VERSION 5.7 ;
  NOWIREEXTENSIONATPIN ON ;
  DIVIDERCHAR "/" ;
  BUSBITCHARS "[]" ;
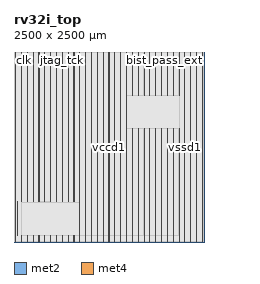
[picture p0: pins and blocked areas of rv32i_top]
MACRO rv32i_top
  CLASS BLOCK ;
  FOREIGN rv32i_top ;
  ORIGIN 0.000 0.000 ;
  SIZE 2500.000 BY 2500.000 ;
  PIN bist_done_ext
    DIRECTION OUTPUT TRISTATE ;
    USE SIGNAL ;
    ANTENNADIFFAREA 0.795200 ;
    PORT
      LAYER met2 ;
        RECT 2123.910 2496.000 2124.190 2500.000 ;
    END
  END bist_done_ext
  PIN bist_mode_ext
    DIRECTION INPUT ;
    USE SIGNAL ;
    ANTENNAGATEAREA 0.990000 ;
    PORT
      LAYER met2 ;
        RECT 1874.130 2496.000 1874.410 2500.000 ;
    END
  END bist_mode_ext
  PIN bist_pass_ext
    DIRECTION OUTPUT TRISTATE ;
    USE SIGNAL ;
    ANTENNADIFFAREA 0.795200 ;
    PORT
      LAYER met2 ;
        RECT 2373.690 2496.000 2373.970 2500.000 ;
    END
  END bist_pass_ext
  PIN clk
    DIRECTION INPUT ;
    USE SIGNAL ;
    ANTENNAGATEAREA 2.156100 ;
    ANTENNADIFFAREA 1.304100 ;
    PORT
      LAYER met2 ;
        RECT 125.670 2496.000 125.950 2500.000 ;
    END
  END clk
  PIN jtag_tck
    DIRECTION INPUT ;
    USE SIGNAL ;
    ANTENNAGATEAREA 0.990000 ;
    PORT
      LAYER met2 ;
        RECT 625.230 2496.000 625.510 2500.000 ;
    END
  END jtag_tck
  PIN jtag_tdi
    DIRECTION INPUT ;
    USE SIGNAL ;
    ANTENNAGATEAREA 0.742500 ;
    PORT
      LAYER met2 ;
        RECT 1124.790 2496.000 1125.070 2500.000 ;
    END
  END jtag_tdi
  PIN jtag_tdo
    DIRECTION OUTPUT TRISTATE ;
    USE SIGNAL ;
    ANTENNADIFFAREA 0.795200 ;
    PORT
      LAYER met2 ;
        RECT 1374.570 2496.000 1374.850 2500.000 ;
    END
  END jtag_tdo
  PIN jtag_tms
    DIRECTION INPUT ;
    USE SIGNAL ;
    ANTENNAGATEAREA 0.742500 ;
    PORT
      LAYER met2 ;
        RECT 875.010 2496.000 875.290 2500.000 ;
    END
  END jtag_tms
  PIN jtag_trst_n
    DIRECTION INPUT ;
    USE SIGNAL ;
    ANTENNAGATEAREA 0.990000 ;
    PORT
      LAYER met2 ;
        RECT 1624.350 2496.000 1624.630 2500.000 ;
    END
  END jtag_trst_n
  PIN rst_n
    DIRECTION INPUT ;
    USE SIGNAL ;
    ANTENNAGATEAREA 0.742500 ;
    PORT
      LAYER met2 ;
        RECT 375.450 2496.000 375.730 2500.000 ;
    END
  END rst_n
  PIN vccd1
    DIRECTION INOUT ;
    USE POWER ;
    PORT
      LAYER met4 ;
        RECT 21.040 10.640 22.640 2489.040 ;
    END
    PORT
      LAYER met4 ;
        RECT 174.640 10.640 176.240 90.020 ;
    END
    PORT
      LAYER met4 ;
        RECT 174.640 526.520 176.240 2489.040 ;
    END
    PORT
      LAYER met4 ;
        RECT 328.240 10.640 329.840 89.400 ;
    END
    PORT
      LAYER met4 ;
        RECT 328.240 526.520 329.840 2489.040 ;
    END
    PORT
      LAYER met4 ;
        RECT 481.840 10.640 483.440 90.020 ;
    END
    PORT
      LAYER met4 ;
        RECT 481.840 526.520 483.440 2489.040 ;
    END
    PORT
      LAYER met4 ;
        RECT 635.440 10.640 637.040 90.020 ;
    END
    PORT
      LAYER met4 ;
        RECT 635.440 526.520 637.040 2489.040 ;
    END
    PORT
      LAYER met4 ;
        RECT 789.040 10.640 790.640 90.020 ;
    END
    PORT
      LAYER met4 ;
        RECT 789.040 526.520 790.640 2489.040 ;
    END
    PORT
      LAYER met4 ;
        RECT 942.640 10.640 944.240 2489.040 ;
    END
    PORT
      LAYER met4 ;
        RECT 1096.240 10.640 1097.840 2489.040 ;
    END
    PORT
      LAYER met4 ;
        RECT 1249.840 10.640 1251.440 2489.040 ;
    END
    PORT
      LAYER met4 ;
        RECT 1403.440 10.640 1405.040 2489.040 ;
    END
    PORT
      LAYER met4 ;
        RECT 1557.040 10.640 1558.640 1490.020 ;
    END
    PORT
      LAYER met4 ;
        RECT 1557.040 1926.520 1558.640 2489.040 ;
    END
    PORT
      LAYER met4 ;
        RECT 1710.640 10.640 1712.240 1490.020 ;
    END
    PORT
      LAYER met4 ;
        RECT 1710.640 1926.520 1712.240 2489.040 ;
    END
    PORT
      LAYER met4 ;
        RECT 1864.240 10.640 1865.840 1490.020 ;
    END
    PORT
      LAYER met4 ;
        RECT 1864.240 1926.520 1865.840 2489.040 ;
    END
    PORT
      LAYER met4 ;
        RECT 2017.840 10.640 2019.440 1490.020 ;
    END
    PORT
      LAYER met4 ;
        RECT 2017.840 1926.520 2019.440 2489.040 ;
    END
    PORT
      LAYER met4 ;
        RECT 2171.440 10.640 2173.040 1490.020 ;
    END
    PORT
      LAYER met4 ;
        RECT 2171.440 1926.520 2173.040 2489.040 ;
    END
    PORT
      LAYER met4 ;
        RECT 2325.040 10.640 2326.640 2489.040 ;
    END
    PORT
      LAYER met4 ;
        RECT 2478.640 10.640 2480.240 2489.040 ;
    END
  END vccd1
  PIN vssd1
    DIRECTION INOUT ;
    USE GROUND ;
    PORT
      LAYER met4 ;
        RECT 97.840 10.640 99.440 90.020 ;
    END
    PORT
      LAYER met4 ;
        RECT 97.840 526.520 99.440 2489.040 ;
    END
    PORT
      LAYER met4 ;
        RECT 251.440 10.640 253.040 90.020 ;
    END
    PORT
      LAYER met4 ;
        RECT 251.440 526.520 253.040 2489.040 ;
    END
    PORT
      LAYER met4 ;
        RECT 405.040 10.640 406.640 89.400 ;
    END
    PORT
      LAYER met4 ;
        RECT 405.040 527.140 406.640 2489.040 ;
    END
    PORT
      LAYER met4 ;
        RECT 558.640 10.640 560.240 90.020 ;
    END
    PORT
      LAYER met4 ;
        RECT 558.640 526.520 560.240 2489.040 ;
    END
    PORT
      LAYER met4 ;
        RECT 712.240 10.640 713.840 90.020 ;
    END
    PORT
      LAYER met4 ;
        RECT 712.240 526.520 713.840 2489.040 ;
    END
    PORT
      LAYER met4 ;
        RECT 865.840 10.640 867.440 2489.040 ;
    END
    PORT
      LAYER met4 ;
        RECT 1019.440 10.640 1021.040 2489.040 ;
    END
    PORT
      LAYER met4 ;
        RECT 1173.040 10.640 1174.640 2489.040 ;
    END
    PORT
      LAYER met4 ;
        RECT 1326.640 10.640 1328.240 2489.040 ;
    END
    PORT
      LAYER met4 ;
        RECT 1480.240 10.640 1481.840 2489.040 ;
    END
    PORT
      LAYER met4 ;
        RECT 1633.840 10.640 1635.440 1490.020 ;
    END
    PORT
      LAYER met4 ;
        RECT 1633.840 1926.520 1635.440 2489.040 ;
    END
    PORT
      LAYER met4 ;
        RECT 1787.440 10.640 1789.040 1490.020 ;
    END
    PORT
      LAYER met4 ;
        RECT 1787.440 1926.520 1789.040 2489.040 ;
    END
    PORT
      LAYER met4 ;
        RECT 1941.040 10.640 1942.640 1489.400 ;
    END
    PORT
      LAYER met4 ;
        RECT 1941.040 1927.140 1942.640 2489.040 ;
    END
    PORT
      LAYER met4 ;
        RECT 2094.640 10.640 2096.240 1490.020 ;
    END
    PORT
      LAYER met4 ;
        RECT 2094.640 1926.520 2096.240 2489.040 ;
    END
    PORT
      LAYER met4 ;
        RECT 2248.240 10.640 2249.840 2489.040 ;
    END
    PORT
      LAYER met4 ;
        RECT 2401.840 10.640 2403.440 2489.040 ;
    END
    PORT
      LAYER met4 ;
        RECT 46.580 86.800 48.180 527.920 ;
    END
  END vssd1
  OBS
      LAYER nwell ;
        RECT 5.330 2487.385 2494.310 2488.990 ;
        RECT 5.330 2481.945 2494.310 2484.775 ;
        RECT 5.330 2476.505 2494.310 2479.335 ;
        RECT 5.330 2471.065 2494.310 2473.895 ;
        RECT 5.330 2465.625 2494.310 2468.455 ;
        RECT 5.330 2460.185 2494.310 2463.015 ;
        RECT 5.330 2454.745 2494.310 2457.575 ;
        RECT 5.330 2449.305 2494.310 2452.135 ;
        RECT 5.330 2443.865 2494.310 2446.695 ;
        RECT 5.330 2438.425 2494.310 2441.255 ;
        RECT 5.330 2432.985 2494.310 2435.815 ;
        RECT 5.330 2427.545 2494.310 2430.375 ;
        RECT 5.330 2422.105 2494.310 2424.935 ;
        RECT 5.330 2416.665 2494.310 2419.495 ;
        RECT 5.330 2411.225 2494.310 2414.055 ;
        RECT 5.330 2405.785 2494.310 2408.615 ;
        RECT 5.330 2400.345 2494.310 2403.175 ;
        RECT 5.330 2394.905 2494.310 2397.735 ;
        RECT 5.330 2389.465 2494.310 2392.295 ;
        RECT 5.330 2384.025 2494.310 2386.855 ;
        RECT 5.330 2378.585 2494.310 2381.415 ;
        RECT 5.330 2373.145 2494.310 2375.975 ;
        RECT 5.330 2367.705 2494.310 2370.535 ;
        RECT 5.330 2362.265 2494.310 2365.095 ;
        RECT 5.330 2356.825 2494.310 2359.655 ;
        RECT 5.330 2351.385 2494.310 2354.215 ;
        RECT 5.330 2345.945 2494.310 2348.775 ;
        RECT 5.330 2340.505 2494.310 2343.335 ;
        RECT 5.330 2335.065 2494.310 2337.895 ;
        RECT 5.330 2329.625 2494.310 2332.455 ;
        RECT 5.330 2324.185 2494.310 2327.015 ;
        RECT 5.330 2318.745 2494.310 2321.575 ;
        RECT 5.330 2313.305 2494.310 2316.135 ;
        RECT 5.330 2307.865 2494.310 2310.695 ;
        RECT 5.330 2302.425 2494.310 2305.255 ;
        RECT 5.330 2296.985 2494.310 2299.815 ;
        RECT 5.330 2291.545 2494.310 2294.375 ;
        RECT 5.330 2286.105 2494.310 2288.935 ;
        RECT 5.330 2280.665 2494.310 2283.495 ;
        RECT 5.330 2275.225 2494.310 2278.055 ;
        RECT 5.330 2269.785 2494.310 2272.615 ;
        RECT 5.330 2264.345 2494.310 2267.175 ;
        RECT 5.330 2258.905 2494.310 2261.735 ;
        RECT 5.330 2253.465 2494.310 2256.295 ;
        RECT 5.330 2248.025 2494.310 2250.855 ;
        RECT 5.330 2242.585 2494.310 2245.415 ;
        RECT 5.330 2237.145 2494.310 2239.975 ;
        RECT 5.330 2231.705 2494.310 2234.535 ;
        RECT 5.330 2226.265 2494.310 2229.095 ;
        RECT 5.330 2220.825 2494.310 2223.655 ;
        RECT 5.330 2215.385 2494.310 2218.215 ;
        RECT 5.330 2209.945 2494.310 2212.775 ;
        RECT 5.330 2204.505 2494.310 2207.335 ;
        RECT 5.330 2199.065 2494.310 2201.895 ;
        RECT 5.330 2193.625 2494.310 2196.455 ;
        RECT 5.330 2188.185 2494.310 2191.015 ;
        RECT 5.330 2182.745 2494.310 2185.575 ;
        RECT 5.330 2177.305 2494.310 2180.135 ;
        RECT 5.330 2171.865 2494.310 2174.695 ;
        RECT 5.330 2166.425 2494.310 2169.255 ;
        RECT 5.330 2160.985 2494.310 2163.815 ;
        RECT 5.330 2155.545 2494.310 2158.375 ;
        RECT 5.330 2150.105 2494.310 2152.935 ;
        RECT 5.330 2144.665 2494.310 2147.495 ;
        RECT 5.330 2139.225 2494.310 2142.055 ;
        RECT 5.330 2133.785 2494.310 2136.615 ;
        RECT 5.330 2128.345 2494.310 2131.175 ;
        RECT 5.330 2122.905 2494.310 2125.735 ;
        RECT 5.330 2117.465 2494.310 2120.295 ;
        RECT 5.330 2112.025 2494.310 2114.855 ;
        RECT 5.330 2106.585 2494.310 2109.415 ;
        RECT 5.330 2101.145 2494.310 2103.975 ;
        RECT 5.330 2095.705 2494.310 2098.535 ;
        RECT 5.330 2090.265 2494.310 2093.095 ;
        RECT 5.330 2084.825 2494.310 2087.655 ;
        RECT 5.330 2079.385 2494.310 2082.215 ;
        RECT 5.330 2073.945 2494.310 2076.775 ;
        RECT 5.330 2068.505 2494.310 2071.335 ;
        RECT 5.330 2063.065 2494.310 2065.895 ;
        RECT 5.330 2057.625 2494.310 2060.455 ;
        RECT 5.330 2052.185 2494.310 2055.015 ;
        RECT 5.330 2046.745 2494.310 2049.575 ;
        RECT 5.330 2041.305 2494.310 2044.135 ;
        RECT 5.330 2035.865 2494.310 2038.695 ;
        RECT 5.330 2030.425 2494.310 2033.255 ;
        RECT 5.330 2024.985 2494.310 2027.815 ;
        RECT 5.330 2019.545 2494.310 2022.375 ;
        RECT 5.330 2014.105 2494.310 2016.935 ;
        RECT 5.330 2008.665 2494.310 2011.495 ;
        RECT 5.330 2003.225 2494.310 2006.055 ;
        RECT 5.330 1997.785 2494.310 2000.615 ;
        RECT 5.330 1992.345 2494.310 1995.175 ;
        RECT 5.330 1986.905 2494.310 1989.735 ;
        RECT 5.330 1981.465 2494.310 1984.295 ;
        RECT 5.330 1976.025 2494.310 1978.855 ;
        RECT 5.330 1970.585 2494.310 1973.415 ;
        RECT 5.330 1965.145 2494.310 1967.975 ;
        RECT 5.330 1959.705 2494.310 1962.535 ;
        RECT 5.330 1954.265 2494.310 1957.095 ;
        RECT 5.330 1948.825 2494.310 1951.655 ;
        RECT 5.330 1943.385 2494.310 1946.215 ;
        RECT 5.330 1937.945 2494.310 1940.775 ;
        RECT 5.330 1932.505 2494.310 1935.335 ;
        RECT 5.330 1928.290 2494.310 1929.895 ;
        RECT 5.330 1927.065 1490.130 1928.290 ;
        RECT 5.330 1921.625 1490.130 1924.455 ;
        RECT 5.330 1916.185 1490.130 1919.015 ;
        RECT 5.330 1910.745 1490.130 1913.575 ;
        RECT 5.330 1905.305 1490.130 1908.135 ;
        RECT 5.330 1899.865 1490.130 1902.695 ;
        RECT 5.330 1894.425 1490.130 1897.255 ;
        RECT 5.330 1888.985 1490.130 1891.815 ;
        RECT 5.330 1883.545 1490.130 1886.375 ;
        RECT 5.330 1878.105 1490.130 1880.935 ;
        RECT 5.330 1872.665 1490.130 1875.495 ;
        RECT 5.330 1867.225 1490.130 1870.055 ;
        RECT 5.330 1861.785 1490.130 1864.615 ;
        RECT 5.330 1856.345 1490.130 1859.175 ;
        RECT 5.330 1850.905 1490.130 1853.735 ;
        RECT 5.330 1845.465 1490.130 1848.295 ;
        RECT 5.330 1840.025 1490.130 1842.855 ;
        RECT 5.330 1834.585 1490.130 1837.415 ;
        RECT 5.330 1829.145 1490.130 1831.975 ;
        RECT 5.330 1823.705 1490.130 1826.535 ;
        RECT 5.330 1818.265 1490.130 1821.095 ;
        RECT 5.330 1812.825 1490.130 1815.655 ;
        RECT 5.330 1807.385 1490.130 1810.215 ;
        RECT 5.330 1801.945 1490.130 1804.775 ;
        RECT 5.330 1796.505 1490.130 1799.335 ;
        RECT 5.330 1791.065 1490.130 1793.895 ;
        RECT 5.330 1785.625 1490.130 1788.455 ;
        RECT 5.330 1780.185 1490.130 1783.015 ;
        RECT 5.330 1774.745 1490.130 1777.575 ;
        RECT 5.330 1769.305 1490.130 1772.135 ;
        RECT 5.330 1763.865 1490.130 1766.695 ;
        RECT 5.330 1758.425 1490.130 1761.255 ;
        RECT 5.330 1752.985 1490.130 1755.815 ;
        RECT 5.330 1747.545 1490.130 1750.375 ;
        RECT 5.330 1742.105 1490.130 1744.935 ;
        RECT 5.330 1736.665 1490.130 1739.495 ;
        RECT 5.330 1731.225 1490.130 1734.055 ;
        RECT 5.330 1725.785 1490.130 1728.615 ;
        RECT 5.330 1720.345 1490.130 1723.175 ;
        RECT 5.330 1714.905 1490.130 1717.735 ;
        RECT 5.330 1709.465 1490.130 1712.295 ;
        RECT 5.330 1704.025 1490.130 1706.855 ;
        RECT 5.330 1698.585 1490.130 1701.415 ;
        RECT 5.330 1693.145 1490.130 1695.975 ;
        RECT 5.330 1687.705 1490.130 1690.535 ;
        RECT 5.330 1682.265 1490.130 1685.095 ;
        RECT 5.330 1676.825 1490.130 1679.655 ;
        RECT 5.330 1671.385 1490.130 1674.215 ;
        RECT 5.330 1665.945 1490.130 1668.775 ;
        RECT 5.330 1660.505 1490.130 1663.335 ;
        RECT 5.330 1655.065 1490.130 1657.895 ;
        RECT 5.330 1649.625 1490.130 1652.455 ;
        RECT 5.330 1644.185 1490.130 1647.015 ;
        RECT 5.330 1638.745 1490.130 1641.575 ;
        RECT 5.330 1633.305 1490.130 1636.135 ;
        RECT 5.330 1627.865 1490.130 1630.695 ;
        RECT 5.330 1622.425 1490.130 1625.255 ;
        RECT 5.330 1616.985 1490.130 1619.815 ;
        RECT 5.330 1611.545 1490.130 1614.375 ;
        RECT 5.330 1606.105 1490.130 1608.935 ;
        RECT 5.330 1600.665 1490.130 1603.495 ;
        RECT 5.330 1595.225 1490.130 1598.055 ;
        RECT 5.330 1589.785 1490.130 1592.615 ;
        RECT 5.330 1584.345 1490.130 1587.175 ;
        RECT 5.330 1578.905 1490.130 1581.735 ;
        RECT 5.330 1573.465 1490.130 1576.295 ;
        RECT 5.330 1568.025 1490.130 1570.855 ;
        RECT 5.330 1562.585 1490.130 1565.415 ;
        RECT 5.330 1557.145 1490.130 1559.975 ;
        RECT 5.330 1551.705 1490.130 1554.535 ;
        RECT 5.330 1546.265 1490.130 1549.095 ;
        RECT 5.330 1540.825 1490.130 1543.655 ;
        RECT 5.330 1535.385 1490.130 1538.215 ;
        RECT 5.330 1529.945 1490.130 1532.775 ;
        RECT 5.330 1524.505 1490.130 1527.335 ;
        RECT 5.330 1519.065 1490.130 1521.895 ;
        RECT 5.330 1513.625 1490.130 1516.455 ;
        RECT 5.330 1508.185 1490.130 1511.015 ;
        RECT 5.330 1502.745 1490.130 1505.575 ;
        RECT 5.330 1497.305 1490.130 1500.135 ;
        RECT 5.330 1491.865 1490.130 1494.695 ;
        RECT 5.330 1488.030 1490.130 1489.255 ;
        RECT 5.330 1486.425 2494.310 1488.030 ;
        RECT 5.330 1480.985 2494.310 1483.815 ;
        RECT 5.330 1475.545 2494.310 1478.375 ;
        RECT 5.330 1470.105 2494.310 1472.935 ;
        RECT 5.330 1464.665 2494.310 1467.495 ;
        RECT 5.330 1459.225 2494.310 1462.055 ;
        RECT 5.330 1453.785 2494.310 1456.615 ;
        RECT 5.330 1448.345 2494.310 1451.175 ;
        RECT 5.330 1442.905 2494.310 1445.735 ;
        RECT 5.330 1437.465 2494.310 1440.295 ;
        RECT 5.330 1432.025 2494.310 1434.855 ;
        RECT 5.330 1426.585 2494.310 1429.415 ;
        RECT 5.330 1421.145 2494.310 1423.975 ;
        RECT 5.330 1415.705 2494.310 1418.535 ;
        RECT 5.330 1410.265 2494.310 1413.095 ;
        RECT 5.330 1404.825 2494.310 1407.655 ;
        RECT 5.330 1399.385 2494.310 1402.215 ;
        RECT 5.330 1393.945 2494.310 1396.775 ;
        RECT 5.330 1388.505 2494.310 1391.335 ;
        RECT 5.330 1383.065 2494.310 1385.895 ;
        RECT 5.330 1377.625 2494.310 1380.455 ;
        RECT 5.330 1372.185 2494.310 1375.015 ;
        RECT 5.330 1366.745 2494.310 1369.575 ;
        RECT 5.330 1361.305 2494.310 1364.135 ;
        RECT 5.330 1355.865 2494.310 1358.695 ;
        RECT 5.330 1350.425 2494.310 1353.255 ;
        RECT 5.330 1344.985 2494.310 1347.815 ;
        RECT 5.330 1339.545 2494.310 1342.375 ;
        RECT 5.330 1334.105 2494.310 1336.935 ;
        RECT 5.330 1328.665 2494.310 1331.495 ;
        RECT 5.330 1323.225 2494.310 1326.055 ;
        RECT 5.330 1317.785 2494.310 1320.615 ;
        RECT 5.330 1312.345 2494.310 1315.175 ;
        RECT 5.330 1306.905 2494.310 1309.735 ;
        RECT 5.330 1301.465 2494.310 1304.295 ;
        RECT 5.330 1296.025 2494.310 1298.855 ;
        RECT 5.330 1290.585 2494.310 1293.415 ;
        RECT 5.330 1285.145 2494.310 1287.975 ;
        RECT 5.330 1279.705 2494.310 1282.535 ;
        RECT 5.330 1274.265 2494.310 1277.095 ;
        RECT 5.330 1268.825 2494.310 1271.655 ;
        RECT 5.330 1263.385 2494.310 1266.215 ;
        RECT 5.330 1257.945 2494.310 1260.775 ;
        RECT 5.330 1252.505 2494.310 1255.335 ;
        RECT 5.330 1247.065 2494.310 1249.895 ;
        RECT 5.330 1241.625 2494.310 1244.455 ;
        RECT 5.330 1236.185 2494.310 1239.015 ;
        RECT 5.330 1230.745 2494.310 1233.575 ;
        RECT 5.330 1225.305 2494.310 1228.135 ;
        RECT 5.330 1219.865 2494.310 1222.695 ;
        RECT 5.330 1214.425 2494.310 1217.255 ;
        RECT 5.330 1208.985 2494.310 1211.815 ;
        RECT 5.330 1203.545 2494.310 1206.375 ;
        RECT 5.330 1198.105 2494.310 1200.935 ;
        RECT 5.330 1192.665 2494.310 1195.495 ;
        RECT 5.330 1187.225 2494.310 1190.055 ;
        RECT 5.330 1181.785 2494.310 1184.615 ;
        RECT 5.330 1176.345 2494.310 1179.175 ;
        RECT 5.330 1170.905 2494.310 1173.735 ;
        RECT 5.330 1165.465 2494.310 1168.295 ;
        RECT 5.330 1160.025 2494.310 1162.855 ;
        RECT 5.330 1154.585 2494.310 1157.415 ;
        RECT 5.330 1149.145 2494.310 1151.975 ;
        RECT 5.330 1143.705 2494.310 1146.535 ;
        RECT 5.330 1138.265 2494.310 1141.095 ;
        RECT 5.330 1132.825 2494.310 1135.655 ;
        RECT 5.330 1127.385 2494.310 1130.215 ;
        RECT 5.330 1121.945 2494.310 1124.775 ;
        RECT 5.330 1116.505 2494.310 1119.335 ;
        RECT 5.330 1111.065 2494.310 1113.895 ;
        RECT 5.330 1105.625 2494.310 1108.455 ;
        RECT 5.330 1100.185 2494.310 1103.015 ;
        RECT 5.330 1094.745 2494.310 1097.575 ;
        RECT 5.330 1089.305 2494.310 1092.135 ;
        RECT 5.330 1083.865 2494.310 1086.695 ;
        RECT 5.330 1078.425 2494.310 1081.255 ;
        RECT 5.330 1072.985 2494.310 1075.815 ;
        RECT 5.330 1067.545 2494.310 1070.375 ;
        RECT 5.330 1062.105 2494.310 1064.935 ;
        RECT 5.330 1056.665 2494.310 1059.495 ;
        RECT 5.330 1051.225 2494.310 1054.055 ;
        RECT 5.330 1045.785 2494.310 1048.615 ;
        RECT 5.330 1040.345 2494.310 1043.175 ;
        RECT 5.330 1034.905 2494.310 1037.735 ;
        RECT 5.330 1029.465 2494.310 1032.295 ;
        RECT 5.330 1024.025 2494.310 1026.855 ;
        RECT 5.330 1018.585 2494.310 1021.415 ;
        RECT 5.330 1013.145 2494.310 1015.975 ;
        RECT 5.330 1007.705 2494.310 1010.535 ;
        RECT 5.330 1002.265 2494.310 1005.095 ;
        RECT 5.330 996.825 2494.310 999.655 ;
        RECT 5.330 991.385 2494.310 994.215 ;
        RECT 5.330 985.945 2494.310 988.775 ;
        RECT 5.330 980.505 2494.310 983.335 ;
        RECT 5.330 975.065 2494.310 977.895 ;
        RECT 5.330 969.625 2494.310 972.455 ;
        RECT 5.330 964.185 2494.310 967.015 ;
        RECT 5.330 958.745 2494.310 961.575 ;
        RECT 5.330 953.305 2494.310 956.135 ;
        RECT 5.330 947.865 2494.310 950.695 ;
        RECT 5.330 942.425 2494.310 945.255 ;
        RECT 5.330 936.985 2494.310 939.815 ;
        RECT 5.330 931.545 2494.310 934.375 ;
        RECT 5.330 926.105 2494.310 928.935 ;
        RECT 5.330 920.665 2494.310 923.495 ;
        RECT 5.330 915.225 2494.310 918.055 ;
        RECT 5.330 909.785 2494.310 912.615 ;
        RECT 5.330 904.345 2494.310 907.175 ;
        RECT 5.330 898.905 2494.310 901.735 ;
        RECT 5.330 893.465 2494.310 896.295 ;
        RECT 5.330 888.025 2494.310 890.855 ;
        RECT 5.330 882.585 2494.310 885.415 ;
        RECT 5.330 877.145 2494.310 879.975 ;
        RECT 5.330 871.705 2494.310 874.535 ;
        RECT 5.330 866.265 2494.310 869.095 ;
        RECT 5.330 860.825 2494.310 863.655 ;
        RECT 5.330 855.385 2494.310 858.215 ;
        RECT 5.330 849.945 2494.310 852.775 ;
        RECT 5.330 844.505 2494.310 847.335 ;
        RECT 5.330 839.065 2494.310 841.895 ;
        RECT 5.330 833.625 2494.310 836.455 ;
        RECT 5.330 828.185 2494.310 831.015 ;
        RECT 5.330 822.745 2494.310 825.575 ;
        RECT 5.330 817.305 2494.310 820.135 ;
        RECT 5.330 811.865 2494.310 814.695 ;
        RECT 5.330 806.425 2494.310 809.255 ;
        RECT 5.330 800.985 2494.310 803.815 ;
        RECT 5.330 795.545 2494.310 798.375 ;
        RECT 5.330 790.105 2494.310 792.935 ;
        RECT 5.330 784.665 2494.310 787.495 ;
        RECT 5.330 779.225 2494.310 782.055 ;
        RECT 5.330 773.785 2494.310 776.615 ;
        RECT 5.330 768.345 2494.310 771.175 ;
        RECT 5.330 762.905 2494.310 765.735 ;
        RECT 5.330 757.465 2494.310 760.295 ;
        RECT 5.330 752.025 2494.310 754.855 ;
        RECT 5.330 746.585 2494.310 749.415 ;
        RECT 5.330 741.145 2494.310 743.975 ;
        RECT 5.330 735.705 2494.310 738.535 ;
        RECT 5.330 730.265 2494.310 733.095 ;
        RECT 5.330 724.825 2494.310 727.655 ;
        RECT 5.330 719.385 2494.310 722.215 ;
        RECT 5.330 713.945 2494.310 716.775 ;
        RECT 5.330 708.505 2494.310 711.335 ;
        RECT 5.330 703.065 2494.310 705.895 ;
        RECT 5.330 697.625 2494.310 700.455 ;
        RECT 5.330 692.185 2494.310 695.015 ;
        RECT 5.330 686.745 2494.310 689.575 ;
        RECT 5.330 681.305 2494.310 684.135 ;
        RECT 5.330 675.865 2494.310 678.695 ;
        RECT 5.330 670.425 2494.310 673.255 ;
        RECT 5.330 664.985 2494.310 667.815 ;
        RECT 5.330 659.545 2494.310 662.375 ;
        RECT 5.330 654.105 2494.310 656.935 ;
        RECT 5.330 648.665 2494.310 651.495 ;
        RECT 5.330 643.225 2494.310 646.055 ;
        RECT 5.330 637.785 2494.310 640.615 ;
        RECT 5.330 632.345 2494.310 635.175 ;
        RECT 5.330 626.905 2494.310 629.735 ;
        RECT 5.330 621.465 2494.310 624.295 ;
        RECT 5.330 616.025 2494.310 618.855 ;
        RECT 5.330 610.585 2494.310 613.415 ;
        RECT 5.330 605.145 2494.310 607.975 ;
        RECT 5.330 599.705 2494.310 602.535 ;
        RECT 5.330 594.265 2494.310 597.095 ;
        RECT 5.330 588.825 2494.310 591.655 ;
        RECT 5.330 583.385 2494.310 586.215 ;
        RECT 5.330 577.945 2494.310 580.775 ;
        RECT 5.330 572.505 2494.310 575.335 ;
        RECT 5.330 567.065 2494.310 569.895 ;
        RECT 5.330 561.625 2494.310 564.455 ;
        RECT 5.330 556.185 2494.310 559.015 ;
        RECT 5.330 550.745 2494.310 553.575 ;
        RECT 5.330 545.305 2494.310 548.135 ;
        RECT 5.330 539.865 2494.310 542.695 ;
        RECT 5.330 534.425 2494.310 537.255 ;
        RECT 5.330 528.985 2494.310 531.815 ;
        RECT 5.330 523.545 89.890 526.375 ;
        RECT 5.330 518.105 89.890 520.935 ;
        RECT 5.330 512.665 89.890 515.495 ;
        RECT 5.330 507.225 89.890 510.055 ;
        RECT 5.330 501.785 89.890 504.615 ;
        RECT 5.330 496.345 89.890 499.175 ;
        RECT 5.330 490.905 89.890 493.735 ;
        RECT 5.330 485.465 89.890 488.295 ;
        RECT 5.330 480.025 89.890 482.855 ;
        RECT 5.330 474.585 89.890 477.415 ;
        RECT 5.330 469.145 89.890 471.975 ;
        RECT 5.330 463.705 89.890 466.535 ;
        RECT 5.330 458.265 89.890 461.095 ;
        RECT 5.330 452.825 89.890 455.655 ;
        RECT 5.330 447.385 89.890 450.215 ;
        RECT 5.330 441.945 89.890 444.775 ;
        RECT 5.330 436.505 89.890 439.335 ;
        RECT 5.330 431.065 89.890 433.895 ;
        RECT 5.330 425.625 89.890 428.455 ;
        RECT 5.330 420.185 89.890 423.015 ;
        RECT 5.330 414.745 89.890 417.575 ;
        RECT 5.330 409.305 89.890 412.135 ;
        RECT 5.330 403.865 89.890 406.695 ;
        RECT 5.330 398.425 89.890 401.255 ;
        RECT 5.330 392.985 89.890 395.815 ;
        RECT 5.330 387.545 89.890 390.375 ;
        RECT 5.330 382.105 89.890 384.935 ;
        RECT 5.330 376.665 89.890 379.495 ;
        RECT 5.330 371.225 89.890 374.055 ;
        RECT 5.330 365.785 89.890 368.615 ;
        RECT 5.330 360.345 89.890 363.175 ;
        RECT 5.330 354.905 89.890 357.735 ;
        RECT 5.330 349.465 89.890 352.295 ;
        RECT 5.330 344.025 89.890 346.855 ;
        RECT 5.330 338.585 89.890 341.415 ;
        RECT 5.330 333.145 89.890 335.975 ;
        RECT 5.330 327.705 89.890 330.535 ;
        RECT 5.330 322.265 89.890 325.095 ;
        RECT 5.330 316.825 89.890 319.655 ;
        RECT 5.330 311.385 89.890 314.215 ;
        RECT 5.330 305.945 89.890 308.775 ;
        RECT 5.330 300.505 89.890 303.335 ;
        RECT 5.330 295.065 89.890 297.895 ;
        RECT 5.330 289.625 89.890 292.455 ;
        RECT 5.330 284.185 89.890 287.015 ;
        RECT 5.330 278.745 89.890 281.575 ;
        RECT 5.330 273.305 89.890 276.135 ;
        RECT 5.330 267.865 89.890 270.695 ;
        RECT 5.330 262.425 89.890 265.255 ;
        RECT 5.330 256.985 89.890 259.815 ;
        RECT 5.330 251.545 89.890 254.375 ;
        RECT 5.330 246.105 89.890 248.935 ;
        RECT 5.330 240.665 89.890 243.495 ;
        RECT 5.330 235.225 89.890 238.055 ;
        RECT 5.330 229.785 89.890 232.615 ;
        RECT 5.330 224.345 89.890 227.175 ;
        RECT 5.330 218.905 89.890 221.735 ;
        RECT 5.330 213.465 89.890 216.295 ;
        RECT 5.330 208.025 89.890 210.855 ;
        RECT 5.330 202.585 89.890 205.415 ;
        RECT 5.330 197.145 89.890 199.975 ;
        RECT 5.330 191.705 89.890 194.535 ;
        RECT 5.330 186.265 89.890 189.095 ;
        RECT 5.330 180.825 89.890 183.655 ;
        RECT 5.330 175.385 89.890 178.215 ;
        RECT 5.330 169.945 89.890 172.775 ;
        RECT 5.330 164.505 89.890 167.335 ;
        RECT 5.330 159.065 89.890 161.895 ;
        RECT 5.330 153.625 89.890 156.455 ;
        RECT 5.330 148.185 89.890 151.015 ;
        RECT 5.330 142.745 89.890 145.575 ;
        RECT 5.330 137.305 89.890 140.135 ;
        RECT 5.330 131.865 89.890 134.695 ;
        RECT 5.330 126.425 89.890 129.255 ;
        RECT 5.330 120.985 89.890 123.815 ;
        RECT 5.330 115.545 89.890 118.375 ;
        RECT 5.330 110.105 89.890 112.935 ;
        RECT 5.330 104.665 89.890 107.495 ;
        RECT 5.330 99.225 89.890 102.055 ;
        RECT 5.330 93.785 89.890 96.615 ;
        RECT 5.330 89.950 89.890 91.175 ;
        RECT 5.330 88.345 2494.310 89.950 ;
        RECT 5.330 82.905 2494.310 85.735 ;
        RECT 5.330 77.465 2494.310 80.295 ;
        RECT 5.330 72.025 2494.310 74.855 ;
        RECT 5.330 66.585 2494.310 69.415 ;
        RECT 5.330 61.145 2494.310 63.975 ;
        RECT 5.330 55.705 2494.310 58.535 ;
        RECT 5.330 50.265 2494.310 53.095 ;
        RECT 5.330 44.825 2494.310 47.655 ;
        RECT 5.330 39.385 2494.310 42.215 ;
        RECT 5.330 33.945 2494.310 36.775 ;
        RECT 5.330 28.505 2494.310 31.335 ;
        RECT 5.330 23.065 2494.310 25.895 ;
        RECT 5.330 17.625 2494.310 20.455 ;
        RECT 5.330 12.185 2494.310 15.015 ;
      LAYER li1 ;
        RECT 5.520 10.795 2494.120 2488.885 ;
      LAYER met1 ;
        RECT 5.520 10.640 2494.120 2489.040 ;
      LAYER met2 ;
        RECT 21.070 2495.720 125.390 2496.690 ;
        RECT 126.230 2495.720 375.170 2496.690 ;
        RECT 376.010 2495.720 624.950 2496.690 ;
        RECT 625.790 2495.720 874.730 2496.690 ;
        RECT 875.570 2495.720 1124.510 2496.690 ;
        RECT 1125.350 2495.720 1374.290 2496.690 ;
        RECT 1375.130 2495.720 1624.070 2496.690 ;
        RECT 1624.910 2495.720 1873.850 2496.690 ;
        RECT 1874.690 2495.720 2123.630 2496.690 ;
        RECT 2124.470 2495.720 2373.410 2496.690 ;
        RECT 2374.250 2495.720 2480.210 2496.690 ;
        RECT 21.070 10.695 2480.210 2495.720 ;
      LAYER met3 ;
        RECT 21.050 10.715 2480.230 2488.965 ;
      LAYER met4 ;
        RECT 100.620 526.120 174.240 2487.265 ;
        RECT 176.640 526.120 251.040 2487.265 ;
        RECT 253.440 526.120 327.840 2487.265 ;
        RECT 330.240 526.740 404.640 2487.265 ;
        RECT 407.040 526.740 481.440 2487.265 ;
        RECT 330.240 526.120 481.440 526.740 ;
        RECT 483.840 526.120 558.240 2487.265 ;
        RECT 560.640 526.120 635.040 2487.265 ;
        RECT 637.440 526.120 711.840 2487.265 ;
        RECT 714.240 526.120 788.640 2487.265 ;
        RECT 791.040 526.120 865.440 2487.265 ;
        RECT 100.620 90.420 865.440 526.120 ;
        RECT 100.620 85.175 174.240 90.420 ;
        RECT 176.640 85.175 251.040 90.420 ;
        RECT 253.440 89.800 481.440 90.420 ;
        RECT 253.440 85.175 327.840 89.800 ;
        RECT 330.240 85.175 404.640 89.800 ;
        RECT 407.040 85.175 481.440 89.800 ;
        RECT 483.840 85.175 558.240 90.420 ;
        RECT 560.640 85.175 635.040 90.420 ;
        RECT 637.440 85.175 711.840 90.420 ;
        RECT 714.240 85.175 788.640 90.420 ;
        RECT 791.040 85.175 865.440 90.420 ;
        RECT 867.840 85.175 942.240 2487.265 ;
        RECT 944.640 85.175 1019.040 2487.265 ;
        RECT 1021.440 85.175 1095.840 2487.265 ;
        RECT 1098.240 85.175 1172.640 2487.265 ;
        RECT 1175.040 85.175 1249.440 2487.265 ;
        RECT 1251.840 85.175 1326.240 2487.265 ;
        RECT 1328.640 85.175 1403.040 2487.265 ;
        RECT 1405.440 85.175 1479.840 2487.265 ;
        RECT 1482.240 1926.120 1556.640 2487.265 ;
        RECT 1559.040 1926.120 1633.440 2487.265 ;
        RECT 1635.840 1926.120 1710.240 2487.265 ;
        RECT 1712.640 1926.120 1787.040 2487.265 ;
        RECT 1789.440 1926.120 1863.840 2487.265 ;
        RECT 1866.240 1926.740 1940.640 2487.265 ;
        RECT 1943.040 1926.740 2017.440 2487.265 ;
        RECT 1866.240 1926.120 2017.440 1926.740 ;
        RECT 2019.840 1926.120 2094.240 2487.265 ;
        RECT 2096.640 1926.120 2171.040 2487.265 ;
        RECT 2173.440 1926.120 2182.480 2487.265 ;
        RECT 1482.240 1490.420 2182.480 1926.120 ;
        RECT 1482.240 85.175 1556.640 1490.420 ;
        RECT 1559.040 85.175 1633.440 1490.420 ;
        RECT 1635.840 85.175 1710.240 1490.420 ;
        RECT 1712.640 85.175 1787.040 1490.420 ;
        RECT 1789.440 85.175 1863.840 1490.420 ;
        RECT 1866.240 1489.800 2017.440 1490.420 ;
        RECT 1866.240 85.175 1940.640 1489.800 ;
        RECT 1943.040 85.175 2017.440 1489.800 ;
        RECT 2019.840 85.175 2094.240 1490.420 ;
        RECT 2096.640 85.175 2171.040 1490.420 ;
        RECT 2173.440 85.175 2182.480 1490.420 ;
  END
END rv32i_top
END LIBRARY

